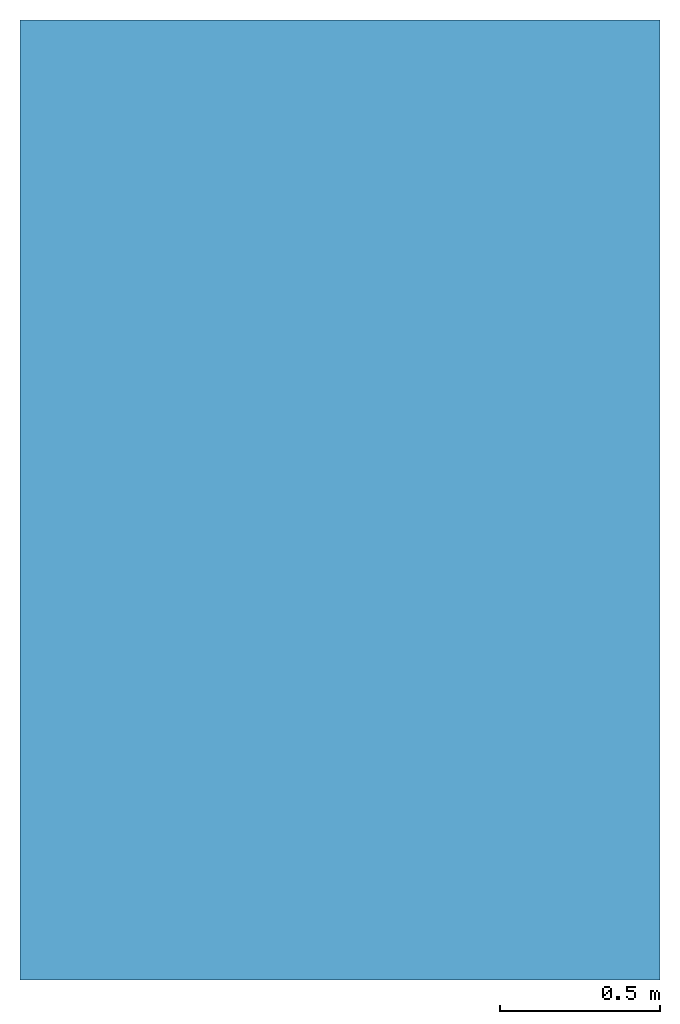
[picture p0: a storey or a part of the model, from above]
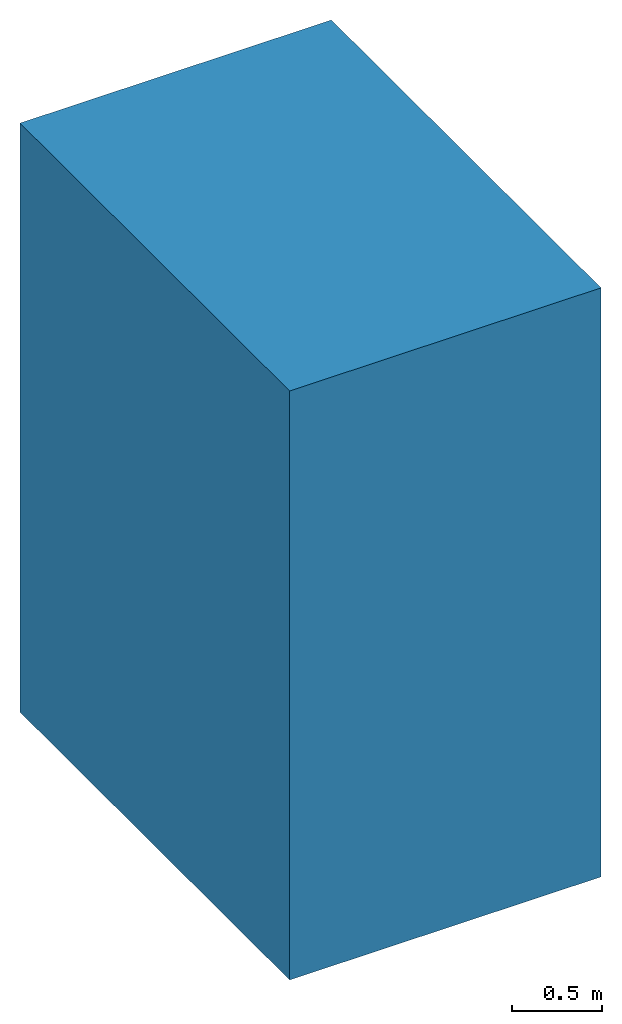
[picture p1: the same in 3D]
Properties of the parts of a building model (IFC4)

# File
File name: IfcSlab-source.ifc
Time: 2026-10-11T04:30:31
Author: IngeTrazo
Organization: IngeTrazo
Written by: IngeTrazo
Made in: IngeTrazo

# IfcBuildingStorey, Storey
In: Building
Elevation: 0 m

# IfcSlab, Muro de José IfcSlab
In: Storey
Qto_SlabBaseQuantities - Perimeter: 14 m; Width: 2 m; GrossArea: 12 m2; NetArea: 12 m2; GrossVolume: 24 m3
